VERSION 5.7 ;
  NOWIREEXTENSIONATPIN ON ;
  DIVIDERCHAR "/" ;
  BUSBITCHARS "[]" ;
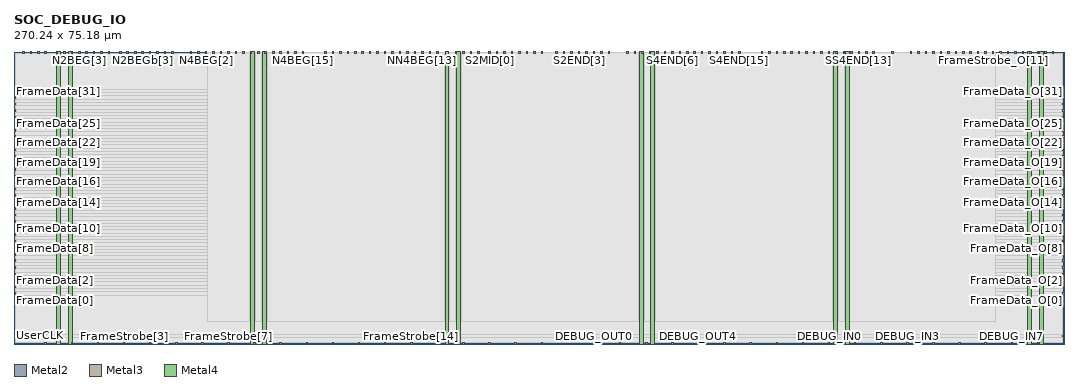
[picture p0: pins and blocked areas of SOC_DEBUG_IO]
MACRO SOC_DEBUG_IO
  CLASS BLOCK ;
  FOREIGN SOC_DEBUG_IO ;
  ORIGIN 0.000 0.000 ;
  SIZE 270.240 BY 75.180 ;
  PIN Co
    DIRECTION OUTPUT ;
    USE SIGNAL ;
    ANTENNADIFFAREA 2.314600 ;
    PORT
      LAYER Metal2 ;
        RECT 225.880 74.780 226.280 75.180 ;
    END
  END Co
  PIN DEBUG_IN0
    DIRECTION OUTPUT ;
    USE SIGNAL ;
    ANTENNADIFFAREA 2.647800 ;
    PORT
      LAYER Metal2 ;
        RECT 209.560 0.000 209.960 0.400 ;
    END
  END DEBUG_IN0
  PIN DEBUG_IN1
    DIRECTION OUTPUT ;
    USE SIGNAL ;
    ANTENNADIFFAREA 2.647800 ;
    PORT
      LAYER Metal2 ;
        RECT 216.280 0.000 216.680 0.400 ;
    END
  END DEBUG_IN1
  PIN DEBUG_IN2
    DIRECTION OUTPUT ;
    USE SIGNAL ;
    ANTENNADIFFAREA 2.647800 ;
    PORT
      LAYER Metal2 ;
        RECT 223.000 0.000 223.400 0.400 ;
    END
  END DEBUG_IN2
  PIN DEBUG_IN3
    DIRECTION OUTPUT ;
    USE SIGNAL ;
    ANTENNADIFFAREA 2.647800 ;
    PORT
      LAYER Metal2 ;
        RECT 229.720 0.000 230.120 0.400 ;
    END
  END DEBUG_IN3
  PIN DEBUG_IN4
    DIRECTION OUTPUT ;
    USE SIGNAL ;
    ANTENNADIFFAREA 2.647800 ;
    PORT
      LAYER Metal2 ;
        RECT 236.440 0.000 236.840 0.400 ;
    END
  END DEBUG_IN4
  PIN DEBUG_IN5
    DIRECTION OUTPUT ;
    USE SIGNAL ;
    ANTENNADIFFAREA 2.647800 ;
    PORT
      LAYER Metal2 ;
        RECT 243.160 0.000 243.560 0.400 ;
    END
  END DEBUG_IN5
  PIN DEBUG_IN6
    DIRECTION OUTPUT ;
    USE SIGNAL ;
    ANTENNADIFFAREA 2.647800 ;
    PORT
      LAYER Metal2 ;
        RECT 249.880 0.000 250.280 0.400 ;
    END
  END DEBUG_IN6
  PIN DEBUG_IN7
    DIRECTION OUTPUT ;
    USE SIGNAL ;
    ANTENNADIFFAREA 2.647800 ;
    PORT
      LAYER Metal2 ;
        RECT 256.600 0.000 257.000 0.400 ;
    END
  END DEBUG_IN7
  PIN DEBUG_OUT0
    DIRECTION INPUT ;
    USE SIGNAL ;
    ANTENNAGATEAREA 0.109200 ;
    ANTENNADIFFAREA 2.015400 ;
    PORT
      LAYER Metal2 ;
        RECT 149.080 0.000 149.480 0.400 ;
    END
  END DEBUG_OUT0
  PIN DEBUG_OUT1
    DIRECTION INPUT ;
    USE SIGNAL ;
    ANTENNAGATEAREA 0.109200 ;
    ANTENNADIFFAREA 2.015400 ;
    PORT
      LAYER Metal2 ;
        RECT 155.800 0.000 156.200 0.400 ;
    END
  END DEBUG_OUT1
  PIN DEBUG_OUT2
    DIRECTION INPUT ;
    USE SIGNAL ;
    ANTENNAGATEAREA 0.109200 ;
    ANTENNADIFFAREA 2.015400 ;
    PORT
      LAYER Metal2 ;
        RECT 162.520 0.000 162.920 0.400 ;
    END
  END DEBUG_OUT2
  PIN DEBUG_OUT3
    DIRECTION INPUT ;
    USE SIGNAL ;
    ANTENNAGATEAREA 0.109200 ;
    ANTENNADIFFAREA 2.015400 ;
    PORT
      LAYER Metal2 ;
        RECT 169.240 0.000 169.640 0.400 ;
    END
  END DEBUG_OUT3
  PIN DEBUG_OUT4
    DIRECTION INPUT ;
    USE SIGNAL ;
    ANTENNAGATEAREA 0.109200 ;
    ANTENNADIFFAREA 2.015400 ;
    PORT
      LAYER Metal2 ;
        RECT 175.960 0.000 176.360 0.400 ;
    END
  END DEBUG_OUT4
  PIN DEBUG_OUT5
    DIRECTION INPUT ;
    USE SIGNAL ;
    ANTENNAGATEAREA 0.109200 ;
    ANTENNADIFFAREA 2.015400 ;
    PORT
      LAYER Metal2 ;
        RECT 182.680 0.000 183.080 0.400 ;
    END
  END DEBUG_OUT5
  PIN DEBUG_OUT6
    DIRECTION INPUT ;
    USE SIGNAL ;
    ANTENNAGATEAREA 0.109200 ;
    ANTENNADIFFAREA 2.015400 ;
    PORT
      LAYER Metal2 ;
        RECT 189.400 0.000 189.800 0.400 ;
    END
  END DEBUG_OUT6
  PIN DEBUG_OUT7
    DIRECTION INPUT ;
    USE SIGNAL ;
    ANTENNAGATEAREA 0.109200 ;
    ANTENNADIFFAREA 2.015400 ;
    PORT
      LAYER Metal2 ;
        RECT 196.120 0.000 196.520 0.400 ;
    END
  END DEBUG_OUT7
  PIN FrameData[0]
    DIRECTION INPUT ;
    USE SIGNAL ;
    ANTENNAGATEAREA 0.722800 ;
    ANTENNADIFFAREA 8.061600 ;
    PORT
      LAYER Metal3 ;
        RECT 0.000 12.820 0.400 13.220 ;
    END
  END FrameData[0]
  PIN FrameData[10]
    DIRECTION INPUT ;
    USE SIGNAL ;
    ANTENNAGATEAREA 0.903500 ;
    ANTENNADIFFAREA 10.077000 ;
    PORT
      LAYER Metal3 ;
        RECT 0.000 29.620 0.400 30.020 ;
    END
  END FrameData[10]
  PIN FrameData[11]
    DIRECTION INPUT ;
    USE SIGNAL ;
    ANTENNAGATEAREA 0.903500 ;
    ANTENNADIFFAREA 10.077000 ;
    PORT
      LAYER Metal3 ;
        RECT 0.000 31.300 0.400 31.700 ;
    END
  END FrameData[11]
  PIN FrameData[12]
    DIRECTION INPUT ;
    USE SIGNAL ;
    ANTENNAGATEAREA 0.903500 ;
    ANTENNADIFFAREA 10.077000 ;
    PORT
      LAYER Metal3 ;
        RECT 0.000 32.980 0.400 33.380 ;
    END
  END FrameData[12]
  PIN FrameData[13]
    DIRECTION INPUT ;
    USE SIGNAL ;
    ANTENNAGATEAREA 0.903500 ;
    ANTENNADIFFAREA 10.077000 ;
    PORT
      LAYER Metal3 ;
        RECT 0.000 34.660 0.400 35.060 ;
    END
  END FrameData[13]
  PIN FrameData[14]
    DIRECTION INPUT ;
    USE SIGNAL ;
    ANTENNAGATEAREA 0.903500 ;
    ANTENNADIFFAREA 10.077000 ;
    PORT
      LAYER Metal3 ;
        RECT 0.000 36.340 0.400 36.740 ;
    END
  END FrameData[14]
  PIN FrameData[15]
    DIRECTION INPUT ;
    USE SIGNAL ;
    ANTENNAGATEAREA 0.903500 ;
    ANTENNADIFFAREA 10.077000 ;
    PORT
      LAYER Metal3 ;
        RECT 0.000 38.020 0.400 38.420 ;
    END
  END FrameData[15]
  PIN FrameData[16]
    DIRECTION INPUT ;
    USE SIGNAL ;
    ANTENNAGATEAREA 0.903500 ;
    ANTENNADIFFAREA 10.077000 ;
    PORT
      LAYER Metal3 ;
        RECT 0.000 39.700 0.400 40.100 ;
    END
  END FrameData[16]
  PIN FrameData[17]
    DIRECTION INPUT ;
    USE SIGNAL ;
    ANTENNAGATEAREA 0.903500 ;
    ANTENNADIFFAREA 10.077000 ;
    PORT
      LAYER Metal3 ;
        RECT 0.000 41.380 0.400 41.780 ;
    END
  END FrameData[17]
  PIN FrameData[18]
    DIRECTION INPUT ;
    USE SIGNAL ;
    ANTENNAGATEAREA 0.903500 ;
    ANTENNADIFFAREA 10.077000 ;
    PORT
      LAYER Metal3 ;
        RECT 0.000 43.060 0.400 43.460 ;
    END
  END FrameData[18]
  PIN FrameData[19]
    DIRECTION INPUT ;
    USE SIGNAL ;
    ANTENNAGATEAREA 0.903500 ;
    ANTENNADIFFAREA 10.077000 ;
    PORT
      LAYER Metal3 ;
        RECT 0.000 44.740 0.400 45.140 ;
    END
  END FrameData[19]
  PIN FrameData[1]
    DIRECTION INPUT ;
    USE SIGNAL ;
    ANTENNAGATEAREA 0.722800 ;
    ANTENNADIFFAREA 8.061600 ;
    PORT
      LAYER Metal3 ;
        RECT 0.000 14.500 0.400 14.900 ;
    END
  END FrameData[1]
  PIN FrameData[20]
    DIRECTION INPUT ;
    USE SIGNAL ;
    ANTENNAGATEAREA 0.903500 ;
    ANTENNADIFFAREA 10.077000 ;
    PORT
      LAYER Metal3 ;
        RECT 0.000 46.420 0.400 46.820 ;
    END
  END FrameData[20]
  PIN FrameData[21]
    DIRECTION INPUT ;
    USE SIGNAL ;
    ANTENNAGATEAREA 0.903500 ;
    ANTENNADIFFAREA 10.077000 ;
    PORT
      LAYER Metal3 ;
        RECT 0.000 48.100 0.400 48.500 ;
    END
  END FrameData[21]
  PIN FrameData[22]
    DIRECTION INPUT ;
    USE SIGNAL ;
    ANTENNAGATEAREA 0.903500 ;
    ANTENNADIFFAREA 10.077000 ;
    PORT
      LAYER Metal3 ;
        RECT 0.000 49.780 0.400 50.180 ;
    END
  END FrameData[22]
  PIN FrameData[23]
    DIRECTION INPUT ;
    USE SIGNAL ;
    ANTENNAGATEAREA 0.903500 ;
    ANTENNADIFFAREA 10.077000 ;
    PORT
      LAYER Metal3 ;
        RECT 0.000 51.460 0.400 51.860 ;
    END
  END FrameData[23]
  PIN FrameData[24]
    DIRECTION INPUT ;
    USE SIGNAL ;
    ANTENNAGATEAREA 0.903500 ;
    ANTENNADIFFAREA 10.077000 ;
    PORT
      LAYER Metal3 ;
        RECT 0.000 53.140 0.400 53.540 ;
    END
  END FrameData[24]
  PIN FrameData[25]
    DIRECTION INPUT ;
    USE SIGNAL ;
    ANTENNAGATEAREA 0.903500 ;
    ANTENNADIFFAREA 10.077000 ;
    PORT
      LAYER Metal3 ;
        RECT 0.000 54.820 0.400 55.220 ;
    END
  END FrameData[25]
  PIN FrameData[26]
    DIRECTION INPUT ;
    USE SIGNAL ;
    ANTENNAGATEAREA 0.903500 ;
    ANTENNADIFFAREA 10.077000 ;
    PORT
      LAYER Metal3 ;
        RECT 0.000 56.500 0.400 56.900 ;
    END
  END FrameData[26]
  PIN FrameData[27]
    DIRECTION INPUT ;
    USE SIGNAL ;
    ANTENNAGATEAREA 0.903500 ;
    ANTENNADIFFAREA 10.077000 ;
    PORT
      LAYER Metal3 ;
        RECT 0.000 58.180 0.400 58.580 ;
    END
  END FrameData[27]
  PIN FrameData[28]
    DIRECTION INPUT ;
    USE SIGNAL ;
    ANTENNAGATEAREA 0.903500 ;
    ANTENNADIFFAREA 10.077000 ;
    PORT
      LAYER Metal3 ;
        RECT 0.000 59.860 0.400 60.260 ;
    END
  END FrameData[28]
  PIN FrameData[29]
    DIRECTION INPUT ;
    USE SIGNAL ;
    ANTENNAGATEAREA 0.903500 ;
    ANTENNADIFFAREA 10.077000 ;
    PORT
      LAYER Metal3 ;
        RECT 0.000 61.540 0.400 61.940 ;
    END
  END FrameData[29]
  PIN FrameData[2]
    DIRECTION INPUT ;
    USE SIGNAL ;
    ANTENNAGATEAREA 0.722800 ;
    ANTENNADIFFAREA 8.061600 ;
    PORT
      LAYER Metal3 ;
        RECT 0.000 16.180 0.400 16.580 ;
    END
  END FrameData[2]
  PIN FrameData[30]
    DIRECTION INPUT ;
    USE SIGNAL ;
    ANTENNAGATEAREA 0.903500 ;
    ANTENNADIFFAREA 10.077000 ;
    PORT
      LAYER Metal3 ;
        RECT 0.000 63.220 0.400 63.620 ;
    END
  END FrameData[30]
  PIN FrameData[31]
    DIRECTION INPUT ;
    USE SIGNAL ;
    ANTENNAGATEAREA 0.903500 ;
    ANTENNADIFFAREA 10.077000 ;
    PORT
      LAYER Metal3 ;
        RECT 0.000 64.900 0.400 65.300 ;
    END
  END FrameData[31]
  PIN FrameData[3]
    DIRECTION INPUT ;
    USE SIGNAL ;
    ANTENNAGATEAREA 0.722800 ;
    ANTENNADIFFAREA 8.061600 ;
    PORT
      LAYER Metal3 ;
        RECT 0.000 17.860 0.400 18.260 ;
    END
  END FrameData[3]
  PIN FrameData[4]
    DIRECTION INPUT ;
    USE SIGNAL ;
    ANTENNAGATEAREA 0.722800 ;
    ANTENNADIFFAREA 8.061600 ;
    PORT
      LAYER Metal3 ;
        RECT 0.000 19.540 0.400 19.940 ;
    END
  END FrameData[4]
  PIN FrameData[5]
    DIRECTION INPUT ;
    USE SIGNAL ;
    ANTENNAGATEAREA 0.722800 ;
    ANTENNADIFFAREA 8.061600 ;
    PORT
      LAYER Metal3 ;
        RECT 0.000 21.220 0.400 21.620 ;
    END
  END FrameData[5]
  PIN FrameData[6]
    DIRECTION INPUT ;
    USE SIGNAL ;
    ANTENNAGATEAREA 0.722800 ;
    ANTENNADIFFAREA 8.061600 ;
    PORT
      LAYER Metal3 ;
        RECT 0.000 22.900 0.400 23.300 ;
    END
  END FrameData[6]
  PIN FrameData[7]
    DIRECTION INPUT ;
    USE SIGNAL ;
    ANTENNAGATEAREA 0.722800 ;
    ANTENNADIFFAREA 8.061600 ;
    PORT
      LAYER Metal3 ;
        RECT 0.000 24.580 0.400 24.980 ;
    END
  END FrameData[7]
  PIN FrameData[8]
    DIRECTION INPUT ;
    USE SIGNAL ;
    ANTENNAGATEAREA 0.722800 ;
    ANTENNADIFFAREA 8.061600 ;
    PORT
      LAYER Metal3 ;
        RECT 0.000 26.260 0.400 26.660 ;
    END
  END FrameData[8]
  PIN FrameData[9]
    DIRECTION INPUT ;
    USE SIGNAL ;
    ANTENNAGATEAREA 0.722800 ;
    ANTENNADIFFAREA 8.061600 ;
    PORT
      LAYER Metal3 ;
        RECT 0.000 27.940 0.400 28.340 ;
    END
  END FrameData[9]
  PIN FrameData_O[0]
    DIRECTION OUTPUT ;
    USE SIGNAL ;
    ANTENNADIFFAREA 2.724000 ;
    PORT
      LAYER Metal3 ;
        RECT 269.840 12.820 270.240 13.220 ;
    END
  END FrameData_O[0]
  PIN FrameData_O[10]
    DIRECTION OUTPUT ;
    USE SIGNAL ;
    ANTENNADIFFAREA 2.724000 ;
    PORT
      LAYER Metal3 ;
        RECT 269.840 29.620 270.240 30.020 ;
    END
  END FrameData_O[10]
  PIN FrameData_O[11]
    DIRECTION OUTPUT ;
    USE SIGNAL ;
    ANTENNADIFFAREA 2.724000 ;
    PORT
      LAYER Metal3 ;
        RECT 269.840 31.300 270.240 31.700 ;
    END
  END FrameData_O[11]
  PIN FrameData_O[12]
    DIRECTION OUTPUT ;
    USE SIGNAL ;
    ANTENNADIFFAREA 2.724000 ;
    PORT
      LAYER Metal3 ;
        RECT 269.840 32.980 270.240 33.380 ;
    END
  END FrameData_O[12]
  PIN FrameData_O[13]
    DIRECTION OUTPUT ;
    USE SIGNAL ;
    ANTENNADIFFAREA 2.724000 ;
    PORT
      LAYER Metal3 ;
        RECT 269.840 34.660 270.240 35.060 ;
    END
  END FrameData_O[13]
  PIN FrameData_O[14]
    DIRECTION OUTPUT ;
    USE SIGNAL ;
    ANTENNADIFFAREA 2.724000 ;
    PORT
      LAYER Metal3 ;
        RECT 269.840 36.340 270.240 36.740 ;
    END
  END FrameData_O[14]
  PIN FrameData_O[15]
    DIRECTION OUTPUT ;
    USE SIGNAL ;
    ANTENNADIFFAREA 2.724000 ;
    PORT
      LAYER Metal3 ;
        RECT 269.840 38.020 270.240 38.420 ;
    END
  END FrameData_O[15]
  PIN FrameData_O[16]
    DIRECTION OUTPUT ;
    USE SIGNAL ;
    ANTENNADIFFAREA 2.724000 ;
    PORT
      LAYER Metal3 ;
        RECT 269.840 39.700 270.240 40.100 ;
    END
  END FrameData_O[16]
  PIN FrameData_O[17]
    DIRECTION OUTPUT ;
    USE SIGNAL ;
    ANTENNADIFFAREA 2.724000 ;
    PORT
      LAYER Metal3 ;
        RECT 269.840 41.380 270.240 41.780 ;
    END
  END FrameData_O[17]
  PIN FrameData_O[18]
    DIRECTION OUTPUT ;
    USE SIGNAL ;
    ANTENNADIFFAREA 2.724000 ;
    PORT
      LAYER Metal3 ;
        RECT 269.840 43.060 270.240 43.460 ;
    END
  END FrameData_O[18]
  PIN FrameData_O[19]
    DIRECTION OUTPUT ;
    USE SIGNAL ;
    ANTENNADIFFAREA 2.724000 ;
    PORT
      LAYER Metal3 ;
        RECT 269.840 44.740 270.240 45.140 ;
    END
  END FrameData_O[19]
  PIN FrameData_O[1]
    DIRECTION OUTPUT ;
    USE SIGNAL ;
    ANTENNADIFFAREA 2.724000 ;
    PORT
      LAYER Metal3 ;
        RECT 269.840 14.500 270.240 14.900 ;
    END
  END FrameData_O[1]
  PIN FrameData_O[20]
    DIRECTION OUTPUT ;
    USE SIGNAL ;
    ANTENNADIFFAREA 2.724000 ;
    PORT
      LAYER Metal3 ;
        RECT 269.840 46.420 270.240 46.820 ;
    END
  END FrameData_O[20]
  PIN FrameData_O[21]
    DIRECTION OUTPUT ;
    USE SIGNAL ;
    ANTENNADIFFAREA 2.724000 ;
    PORT
      LAYER Metal3 ;
        RECT 269.840 48.100 270.240 48.500 ;
    END
  END FrameData_O[21]
  PIN FrameData_O[22]
    DIRECTION OUTPUT ;
    USE SIGNAL ;
    ANTENNADIFFAREA 2.724000 ;
    PORT
      LAYER Metal3 ;
        RECT 269.840 49.780 270.240 50.180 ;
    END
  END FrameData_O[22]
  PIN FrameData_O[23]
    DIRECTION OUTPUT ;
    USE SIGNAL ;
    ANTENNADIFFAREA 2.724000 ;
    PORT
      LAYER Metal3 ;
        RECT 269.840 51.460 270.240 51.860 ;
    END
  END FrameData_O[23]
  PIN FrameData_O[24]
    DIRECTION OUTPUT ;
    USE SIGNAL ;
    ANTENNADIFFAREA 2.724000 ;
    PORT
      LAYER Metal3 ;
        RECT 269.840 53.140 270.240 53.540 ;
    END
  END FrameData_O[24]
  PIN FrameData_O[25]
    DIRECTION OUTPUT ;
    USE SIGNAL ;
    ANTENNADIFFAREA 2.724000 ;
    PORT
      LAYER Metal3 ;
        RECT 269.840 54.820 270.240 55.220 ;
    END
  END FrameData_O[25]
  PIN FrameData_O[26]
    DIRECTION OUTPUT ;
    USE SIGNAL ;
    ANTENNADIFFAREA 2.724000 ;
    PORT
      LAYER Metal3 ;
        RECT 269.840 56.500 270.240 56.900 ;
    END
  END FrameData_O[26]
  PIN FrameData_O[27]
    DIRECTION OUTPUT ;
    USE SIGNAL ;
    ANTENNADIFFAREA 2.724000 ;
    PORT
      LAYER Metal3 ;
        RECT 269.840 58.180 270.240 58.580 ;
    END
  END FrameData_O[27]
  PIN FrameData_O[28]
    DIRECTION OUTPUT ;
    USE SIGNAL ;
    ANTENNADIFFAREA 2.724000 ;
    PORT
      LAYER Metal3 ;
        RECT 269.840 59.860 270.240 60.260 ;
    END
  END FrameData_O[28]
  PIN FrameData_O[29]
    DIRECTION OUTPUT ;
    USE SIGNAL ;
    ANTENNADIFFAREA 2.724000 ;
    PORT
      LAYER Metal3 ;
        RECT 269.840 61.540 270.240 61.940 ;
    END
  END FrameData_O[29]
  PIN FrameData_O[2]
    DIRECTION OUTPUT ;
    USE SIGNAL ;
    ANTENNADIFFAREA 2.724000 ;
    PORT
      LAYER Metal3 ;
        RECT 269.840 16.180 270.240 16.580 ;
    END
  END FrameData_O[2]
  PIN FrameData_O[30]
    DIRECTION OUTPUT ;
    USE SIGNAL ;
    ANTENNADIFFAREA 2.724000 ;
    PORT
      LAYER Metal3 ;
        RECT 269.840 63.220 270.240 63.620 ;
    END
  END FrameData_O[30]
  PIN FrameData_O[31]
    DIRECTION OUTPUT ;
    USE SIGNAL ;
    ANTENNADIFFAREA 2.724000 ;
    PORT
      LAYER Metal3 ;
        RECT 269.840 64.900 270.240 65.300 ;
    END
  END FrameData_O[31]
  PIN FrameData_O[3]
    DIRECTION OUTPUT ;
    USE SIGNAL ;
    ANTENNADIFFAREA 2.724000 ;
    PORT
      LAYER Metal3 ;
        RECT 269.840 17.860 270.240 18.260 ;
    END
  END FrameData_O[3]
  PIN FrameData_O[4]
    DIRECTION OUTPUT ;
    USE SIGNAL ;
    ANTENNADIFFAREA 2.724000 ;
    PORT
      LAYER Metal3 ;
        RECT 269.840 19.540 270.240 19.940 ;
    END
  END FrameData_O[4]
  PIN FrameData_O[5]
    DIRECTION OUTPUT ;
    USE SIGNAL ;
    ANTENNADIFFAREA 2.724000 ;
    PORT
      LAYER Metal3 ;
        RECT 269.840 21.220 270.240 21.620 ;
    END
  END FrameData_O[5]
  PIN FrameData_O[6]
    DIRECTION OUTPUT ;
    USE SIGNAL ;
    ANTENNADIFFAREA 2.724000 ;
    PORT
      LAYER Metal3 ;
        RECT 269.840 22.900 270.240 23.300 ;
    END
  END FrameData_O[6]
  PIN FrameData_O[7]
    DIRECTION OUTPUT ;
    USE SIGNAL ;
    ANTENNADIFFAREA 2.724000 ;
    PORT
      LAYER Metal3 ;
        RECT 269.840 24.580 270.240 24.980 ;
    END
  END FrameData_O[7]
  PIN FrameData_O[8]
    DIRECTION OUTPUT ;
    USE SIGNAL ;
    ANTENNADIFFAREA 2.724000 ;
    PORT
      LAYER Metal3 ;
        RECT 269.840 26.260 270.240 26.660 ;
    END
  END FrameData_O[8]
  PIN FrameData_O[9]
    DIRECTION OUTPUT ;
    USE SIGNAL ;
    ANTENNADIFFAREA 2.724000 ;
    PORT
      LAYER Metal3 ;
        RECT 269.840 27.940 270.240 28.340 ;
    END
  END FrameData_O[9]
  PIN FrameStrobe[0]
    DIRECTION INPUT ;
    USE SIGNAL ;
    ANTENNAGATEAREA 11.745500 ;
    ANTENNADIFFAREA 66.508202 ;
    PORT
      LAYER Metal2 ;
        RECT 7.960 0.000 8.360 0.400 ;
    END
  END FrameStrobe[0]
  PIN FrameStrobe[10]
    DIRECTION INPUT ;
    USE SIGNAL ;
    ANTENNAGATEAREA 0.180700 ;
    ANTENNADIFFAREA 2.015400 ;
    PORT
      LAYER Metal2 ;
        RECT 75.160 0.000 75.560 0.400 ;
    END
  END FrameStrobe[10]
  PIN FrameStrobe[11]
    DIRECTION INPUT ;
    USE SIGNAL ;
    ANTENNAGATEAREA 0.180700 ;
    ANTENNADIFFAREA 2.015400 ;
    PORT
      LAYER Metal2 ;
        RECT 81.880 0.000 82.280 0.400 ;
    END
  END FrameStrobe[11]
  PIN FrameStrobe[12]
    DIRECTION INPUT ;
    USE SIGNAL ;
    ANTENNAGATEAREA 0.180700 ;
    ANTENNADIFFAREA 2.015400 ;
    PORT
      LAYER Metal2 ;
        RECT 88.600 0.000 89.000 0.400 ;
    END
  END FrameStrobe[12]
  PIN FrameStrobe[13]
    DIRECTION INPUT ;
    USE SIGNAL ;
    ANTENNAGATEAREA 0.180700 ;
    ANTENNADIFFAREA 2.015400 ;
    PORT
      LAYER Metal2 ;
        RECT 95.320 0.000 95.720 0.400 ;
    END
  END FrameStrobe[13]
  PIN FrameStrobe[14]
    DIRECTION INPUT ;
    USE SIGNAL ;
    ANTENNAGATEAREA 0.180700 ;
    ANTENNADIFFAREA 2.015400 ;
    PORT
      LAYER Metal2 ;
        RECT 102.040 0.000 102.440 0.400 ;
    END
  END FrameStrobe[14]
  PIN FrameStrobe[15]
    DIRECTION INPUT ;
    USE SIGNAL ;
    ANTENNAGATEAREA 0.180700 ;
    ANTENNADIFFAREA 2.015400 ;
    PORT
      LAYER Metal2 ;
        RECT 108.760 0.000 109.160 0.400 ;
    END
  END FrameStrobe[15]
  PIN FrameStrobe[16]
    DIRECTION INPUT ;
    USE SIGNAL ;
    ANTENNAGATEAREA 0.180700 ;
    ANTENNADIFFAREA 2.015400 ;
    PORT
      LAYER Metal2 ;
        RECT 115.480 0.000 115.880 0.400 ;
    END
  END FrameStrobe[16]
  PIN FrameStrobe[17]
    DIRECTION INPUT ;
    USE SIGNAL ;
    ANTENNAGATEAREA 0.180700 ;
    ANTENNADIFFAREA 2.015400 ;
    PORT
      LAYER Metal2 ;
        RECT 122.200 0.000 122.600 0.400 ;
    END
  END FrameStrobe[17]
  PIN FrameStrobe[18]
    DIRECTION INPUT ;
    USE SIGNAL ;
    ANTENNAGATEAREA 0.180700 ;
    ANTENNADIFFAREA 2.015400 ;
    PORT
      LAYER Metal2 ;
        RECT 128.920 0.000 129.320 0.400 ;
    END
  END FrameStrobe[18]
  PIN FrameStrobe[19]
    DIRECTION INPUT ;
    USE SIGNAL ;
    ANTENNAGATEAREA 0.180700 ;
    ANTENNADIFFAREA 2.015400 ;
    PORT
      LAYER Metal2 ;
        RECT 135.640 0.000 136.040 0.400 ;
    END
  END FrameStrobe[19]
  PIN FrameStrobe[1]
    DIRECTION INPUT ;
    USE SIGNAL ;
    ANTENNAGATEAREA 11.745500 ;
    ANTENNADIFFAREA 66.508202 ;
    PORT
      LAYER Metal2 ;
        RECT 14.680 0.000 15.080 0.400 ;
    END
  END FrameStrobe[1]
  PIN FrameStrobe[2]
    DIRECTION INPUT ;
    USE SIGNAL ;
    ANTENNAGATEAREA 11.745500 ;
    ANTENNADIFFAREA 66.508202 ;
    PORT
      LAYER Metal2 ;
        RECT 21.400 0.000 21.800 0.400 ;
    END
  END FrameStrobe[2]
  PIN FrameStrobe[3]
    DIRECTION INPUT ;
    USE SIGNAL ;
    ANTENNAGATEAREA 8.131500 ;
    ANTENNADIFFAREA 46.354198 ;
    PORT
      LAYER Metal2 ;
        RECT 28.120 0.000 28.520 0.400 ;
    END
  END FrameStrobe[3]
  PIN FrameStrobe[4]
    DIRECTION INPUT ;
    USE SIGNAL ;
    ANTENNAGATEAREA 0.180700 ;
    ANTENNADIFFAREA 2.015400 ;
    PORT
      LAYER Metal2 ;
        RECT 34.840 0.000 35.240 0.400 ;
    END
  END FrameStrobe[4]
  PIN FrameStrobe[5]
    DIRECTION INPUT ;
    USE SIGNAL ;
    ANTENNAGATEAREA 0.180700 ;
    ANTENNADIFFAREA 2.015400 ;
    PORT
      LAYER Metal2 ;
        RECT 41.560 0.000 41.960 0.400 ;
    END
  END FrameStrobe[5]
  PIN FrameStrobe[6]
    DIRECTION INPUT ;
    USE SIGNAL ;
    ANTENNAGATEAREA 0.180700 ;
    ANTENNADIFFAREA 2.015400 ;
    PORT
      LAYER Metal2 ;
        RECT 48.280 0.000 48.680 0.400 ;
    END
  END FrameStrobe[6]
  PIN FrameStrobe[7]
    DIRECTION INPUT ;
    USE SIGNAL ;
    ANTENNAGATEAREA 0.180700 ;
    ANTENNADIFFAREA 2.015400 ;
    PORT
      LAYER Metal2 ;
        RECT 55.000 0.000 55.400 0.400 ;
    END
  END FrameStrobe[7]
  PIN FrameStrobe[8]
    DIRECTION INPUT ;
    USE SIGNAL ;
    ANTENNAGATEAREA 0.180700 ;
    ANTENNADIFFAREA 2.015400 ;
    PORT
      LAYER Metal2 ;
        RECT 61.720 0.000 62.120 0.400 ;
    END
  END FrameStrobe[8]
  PIN FrameStrobe[9]
    DIRECTION INPUT ;
    USE SIGNAL ;
    ANTENNAGATEAREA 0.180700 ;
    ANTENNADIFFAREA 2.015400 ;
    PORT
      LAYER Metal2 ;
        RECT 68.440 0.000 68.840 0.400 ;
    END
  END FrameStrobe[9]
  PIN FrameStrobe_O[0]
    DIRECTION OUTPUT ;
    USE SIGNAL ;
    ANTENNADIFFAREA 2.724000 ;
    PORT
      LAYER Metal2 ;
        RECT 230.680 74.780 231.080 75.180 ;
    END
  END FrameStrobe_O[0]
  PIN FrameStrobe_O[10]
    DIRECTION OUTPUT ;
    USE SIGNAL ;
    ANTENNADIFFAREA 2.724000 ;
    PORT
      LAYER Metal2 ;
        RECT 249.880 74.780 250.280 75.180 ;
    END
  END FrameStrobe_O[10]
  PIN FrameStrobe_O[11]
    DIRECTION OUTPUT ;
    USE SIGNAL ;
    ANTENNADIFFAREA 2.724000 ;
    PORT
      LAYER Metal2 ;
        RECT 251.800 74.780 252.200 75.180 ;
    END
  END FrameStrobe_O[11]
  PIN FrameStrobe_O[12]
    DIRECTION OUTPUT ;
    USE SIGNAL ;
    ANTENNADIFFAREA 2.724000 ;
    PORT
      LAYER Metal2 ;
        RECT 253.720 74.780 254.120 75.180 ;
    END
  END FrameStrobe_O[12]
  PIN FrameStrobe_O[13]
    DIRECTION OUTPUT ;
    USE SIGNAL ;
    ANTENNADIFFAREA 2.724000 ;
    PORT
      LAYER Metal2 ;
        RECT 255.640 74.780 256.040 75.180 ;
    END
  END FrameStrobe_O[13]
  PIN FrameStrobe_O[14]
    DIRECTION OUTPUT ;
    USE SIGNAL ;
    ANTENNADIFFAREA 2.724000 ;
    PORT
      LAYER Metal2 ;
        RECT 257.560 74.780 257.960 75.180 ;
    END
  END FrameStrobe_O[14]
  PIN FrameStrobe_O[15]
    DIRECTION OUTPUT ;
    USE SIGNAL ;
    ANTENNADIFFAREA 2.724000 ;
    PORT
      LAYER Metal2 ;
        RECT 259.480 74.780 259.880 75.180 ;
    END
  END FrameStrobe_O[15]
  PIN FrameStrobe_O[16]
    DIRECTION OUTPUT ;
    USE SIGNAL ;
    ANTENNADIFFAREA 2.724000 ;
    PORT
      LAYER Metal2 ;
        RECT 261.400 74.780 261.800 75.180 ;
    END
  END FrameStrobe_O[16]
  PIN FrameStrobe_O[17]
    DIRECTION OUTPUT ;
    USE SIGNAL ;
    ANTENNADIFFAREA 2.724000 ;
    PORT
      LAYER Metal2 ;
        RECT 263.320 74.780 263.720 75.180 ;
    END
  END FrameStrobe_O[17]
  PIN FrameStrobe_O[18]
    DIRECTION OUTPUT ;
    USE SIGNAL ;
    ANTENNADIFFAREA 2.724000 ;
    PORT
      LAYER Metal2 ;
        RECT 265.240 74.780 265.640 75.180 ;
    END
  END FrameStrobe_O[18]
  PIN FrameStrobe_O[19]
    DIRECTION OUTPUT ;
    USE SIGNAL ;
    ANTENNADIFFAREA 2.724000 ;
    PORT
      LAYER Metal2 ;
        RECT 267.160 74.780 267.560 75.180 ;
    END
  END FrameStrobe_O[19]
  PIN FrameStrobe_O[1]
    DIRECTION OUTPUT ;
    USE SIGNAL ;
    ANTENNADIFFAREA 2.724000 ;
    PORT
      LAYER Metal2 ;
        RECT 232.600 74.780 233.000 75.180 ;
    END
  END FrameStrobe_O[1]
  PIN FrameStrobe_O[2]
    DIRECTION OUTPUT ;
    USE SIGNAL ;
    ANTENNADIFFAREA 2.724000 ;
    PORT
      LAYER Metal2 ;
        RECT 234.520 74.780 234.920 75.180 ;
    END
  END FrameStrobe_O[2]
  PIN FrameStrobe_O[3]
    DIRECTION OUTPUT ;
    USE SIGNAL ;
    ANTENNADIFFAREA 2.724000 ;
    PORT
      LAYER Metal2 ;
        RECT 236.440 74.780 236.840 75.180 ;
    END
  END FrameStrobe_O[3]
  PIN FrameStrobe_O[4]
    DIRECTION OUTPUT ;
    USE SIGNAL ;
    ANTENNADIFFAREA 2.724000 ;
    PORT
      LAYER Metal2 ;
        RECT 238.360 74.780 238.760 75.180 ;
    END
  END FrameStrobe_O[4]
  PIN FrameStrobe_O[5]
    DIRECTION OUTPUT ;
    USE SIGNAL ;
    ANTENNADIFFAREA 2.724000 ;
    PORT
      LAYER Metal2 ;
        RECT 240.280 74.780 240.680 75.180 ;
    END
  END FrameStrobe_O[5]
  PIN FrameStrobe_O[6]
    DIRECTION OUTPUT ;
    USE SIGNAL ;
    ANTENNADIFFAREA 2.724000 ;
    PORT
      LAYER Metal2 ;
        RECT 242.200 74.780 242.600 75.180 ;
    END
  END FrameStrobe_O[6]
  PIN FrameStrobe_O[7]
    DIRECTION OUTPUT ;
    USE SIGNAL ;
    ANTENNADIFFAREA 2.724000 ;
    PORT
      LAYER Metal2 ;
        RECT 244.120 74.780 244.520 75.180 ;
    END
  END FrameStrobe_O[7]
  PIN FrameStrobe_O[8]
    DIRECTION OUTPUT ;
    USE SIGNAL ;
    ANTENNADIFFAREA 2.724000 ;
    PORT
      LAYER Metal2 ;
        RECT 246.040 74.780 246.440 75.180 ;
    END
  END FrameStrobe_O[8]
  PIN FrameStrobe_O[9]
    DIRECTION OUTPUT ;
    USE SIGNAL ;
    ANTENNADIFFAREA 2.724000 ;
    PORT
      LAYER Metal2 ;
        RECT 247.960 74.780 248.360 75.180 ;
    END
  END FrameStrobe_O[9]
  PIN N1BEG[0]
    DIRECTION OUTPUT ;
    USE SIGNAL ;
    ANTENNADIFFAREA 2.724000 ;
    PORT
      LAYER Metal2 ;
        RECT 2.200 74.780 2.600 75.180 ;
    END
  END N1BEG[0]
  PIN N1BEG[1]
    DIRECTION OUTPUT ;
    USE SIGNAL ;
    ANTENNADIFFAREA 2.724000 ;
    PORT
      LAYER Metal2 ;
        RECT 4.120 74.780 4.520 75.180 ;
    END
  END N1BEG[1]
  PIN N1BEG[2]
    DIRECTION OUTPUT ;
    USE SIGNAL ;
    ANTENNADIFFAREA 2.724000 ;
    PORT
      LAYER Metal2 ;
        RECT 6.040 74.780 6.440 75.180 ;
    END
  END N1BEG[2]
  PIN N1BEG[3]
    DIRECTION OUTPUT ;
    USE SIGNAL ;
    ANTENNADIFFAREA 2.724000 ;
    PORT
      LAYER Metal2 ;
        RECT 7.960 74.780 8.360 75.180 ;
    END
  END N1BEG[3]
  PIN N2BEG[0]
    DIRECTION OUTPUT ;
    USE SIGNAL ;
    ANTENNADIFFAREA 2.724000 ;
    PORT
      LAYER Metal2 ;
        RECT 10.840 74.780 11.240 75.180 ;
    END
  END N2BEG[0]
  PIN N2BEG[1]
    DIRECTION OUTPUT ;
    USE SIGNAL ;
    ANTENNADIFFAREA 2.724000 ;
    PORT
      LAYER Metal2 ;
        RECT 12.760 74.780 13.160 75.180 ;
    END
  END N2BEG[1]
  PIN N2BEG[2]
    DIRECTION OUTPUT ;
    USE SIGNAL ;
    ANTENNADIFFAREA 2.724000 ;
    PORT
      LAYER Metal2 ;
        RECT 14.680 74.780 15.080 75.180 ;
    END
  END N2BEG[2]
  PIN N2BEG[3]
    DIRECTION OUTPUT ;
    USE SIGNAL ;
    ANTENNADIFFAREA 2.724000 ;
    PORT
      LAYER Metal2 ;
        RECT 16.600 74.780 17.000 75.180 ;
    END
  END N2BEG[3]
  PIN N2BEG[4]
    DIRECTION OUTPUT ;
    USE SIGNAL ;
    ANTENNADIFFAREA 2.724000 ;
    PORT
      LAYER Metal2 ;
        RECT 18.520 74.780 18.920 75.180 ;
    END
  END N2BEG[4]
  PIN N2BEG[5]
    DIRECTION OUTPUT ;
    USE SIGNAL ;
    ANTENNADIFFAREA 2.724000 ;
    PORT
      LAYER Metal2 ;
        RECT 20.440 74.780 20.840 75.180 ;
    END
  END N2BEG[5]
  PIN N2BEG[6]
    DIRECTION OUTPUT ;
    USE SIGNAL ;
    ANTENNADIFFAREA 2.724000 ;
    PORT
      LAYER Metal2 ;
        RECT 22.360 74.780 22.760 75.180 ;
    END
  END N2BEG[6]
  PIN N2BEG[7]
    DIRECTION OUTPUT ;
    USE SIGNAL ;
    ANTENNADIFFAREA 2.724000 ;
    PORT
      LAYER Metal2 ;
        RECT 24.280 74.780 24.680 75.180 ;
    END
  END N2BEG[7]
  PIN N2BEGb[0]
    DIRECTION OUTPUT ;
    USE SIGNAL ;
    ANTENNADIFFAREA 2.724000 ;
    PORT
      LAYER Metal2 ;
        RECT 27.160 74.780 27.560 75.180 ;
    END
  END N2BEGb[0]
  PIN N2BEGb[1]
    DIRECTION OUTPUT ;
    USE SIGNAL ;
    ANTENNADIFFAREA 2.724000 ;
    PORT
      LAYER Metal2 ;
        RECT 29.080 74.780 29.480 75.180 ;
    END
  END N2BEGb[1]
  PIN N2BEGb[2]
    DIRECTION OUTPUT ;
    USE SIGNAL ;
    ANTENNADIFFAREA 2.724000 ;
    PORT
      LAYER Metal2 ;
        RECT 31.000 74.780 31.400 75.180 ;
    END
  END N2BEGb[2]
  PIN N2BEGb[3]
    DIRECTION OUTPUT ;
    USE SIGNAL ;
    ANTENNADIFFAREA 2.724000 ;
    PORT
      LAYER Metal2 ;
        RECT 32.920 74.780 33.320 75.180 ;
    END
  END N2BEGb[3]
  PIN N2BEGb[4]
    DIRECTION OUTPUT ;
    USE SIGNAL ;
    ANTENNADIFFAREA 2.724000 ;
    PORT
      LAYER Metal2 ;
        RECT 34.840 74.780 35.240 75.180 ;
    END
  END N2BEGb[4]
  PIN N2BEGb[5]
    DIRECTION OUTPUT ;
    USE SIGNAL ;
    ANTENNADIFFAREA 2.724000 ;
    PORT
      LAYER Metal2 ;
        RECT 36.760 74.780 37.160 75.180 ;
    END
  END N2BEGb[5]
  PIN N2BEGb[6]
    DIRECTION OUTPUT ;
    USE SIGNAL ;
    ANTENNADIFFAREA 2.724000 ;
    PORT
      LAYER Metal2 ;
        RECT 38.680 74.780 39.080 75.180 ;
    END
  END N2BEGb[6]
  PIN N2BEGb[7]
    DIRECTION OUTPUT ;
    USE SIGNAL ;
    ANTENNADIFFAREA 2.724000 ;
    PORT
      LAYER Metal2 ;
        RECT 40.600 74.780 41.000 75.180 ;
    END
  END N2BEGb[7]
  PIN N4BEG[0]
    DIRECTION OUTPUT ;
    USE SIGNAL ;
    ANTENNADIFFAREA 2.724000 ;
    PORT
      LAYER Metal2 ;
        RECT 45.400 74.780 45.800 75.180 ;
    END
  END N4BEG[0]
  PIN N4BEG[10]
    DIRECTION OUTPUT ;
    USE SIGNAL ;
    ANTENNADIFFAREA 2.724000 ;
    PORT
      LAYER Metal2 ;
        RECT 64.600 74.780 65.000 75.180 ;
    END
  END N4BEG[10]
  PIN N4BEG[11]
    DIRECTION OUTPUT ;
    USE SIGNAL ;
    ANTENNADIFFAREA 2.724000 ;
    PORT
      LAYER Metal2 ;
        RECT 66.520 74.780 66.920 75.180 ;
    END
  END N4BEG[11]
  PIN N4BEG[12]
    DIRECTION OUTPUT ;
    USE SIGNAL ;
    ANTENNADIFFAREA 2.724000 ;
    PORT
      LAYER Metal2 ;
        RECT 68.440 74.780 68.840 75.180 ;
    END
  END N4BEG[12]
  PIN N4BEG[13]
    DIRECTION OUTPUT ;
    USE SIGNAL ;
    ANTENNADIFFAREA 2.724000 ;
    PORT
      LAYER Metal2 ;
        RECT 70.360 74.780 70.760 75.180 ;
    END
  END N4BEG[13]
  PIN N4BEG[14]
    DIRECTION OUTPUT ;
    USE SIGNAL ;
    ANTENNADIFFAREA 2.724000 ;
    PORT
      LAYER Metal2 ;
        RECT 72.280 74.780 72.680 75.180 ;
    END
  END N4BEG[14]
  PIN N4BEG[15]
    DIRECTION OUTPUT ;
    USE SIGNAL ;
    ANTENNADIFFAREA 2.724000 ;
    PORT
      LAYER Metal2 ;
        RECT 74.200 74.780 74.600 75.180 ;
    END
  END N4BEG[15]
  PIN N4BEG[1]
    DIRECTION OUTPUT ;
    USE SIGNAL ;
    ANTENNADIFFAREA 2.724000 ;
    PORT
      LAYER Metal2 ;
        RECT 47.320 74.780 47.720 75.180 ;
    END
  END N4BEG[1]
  PIN N4BEG[2]
    DIRECTION OUTPUT ;
    USE SIGNAL ;
    ANTENNADIFFAREA 2.724000 ;
    PORT
      LAYER Metal2 ;
        RECT 49.240 74.780 49.640 75.180 ;
    END
  END N4BEG[2]
  PIN N4BEG[3]
    DIRECTION OUTPUT ;
    USE SIGNAL ;
    ANTENNADIFFAREA 2.724000 ;
    PORT
      LAYER Metal2 ;
        RECT 51.160 74.780 51.560 75.180 ;
    END
  END N4BEG[3]
  PIN N4BEG[4]
    DIRECTION OUTPUT ;
    USE SIGNAL ;
    ANTENNADIFFAREA 2.724000 ;
    PORT
      LAYER Metal2 ;
        RECT 53.080 74.780 53.480 75.180 ;
    END
  END N4BEG[4]
  PIN N4BEG[5]
    DIRECTION OUTPUT ;
    USE SIGNAL ;
    ANTENNADIFFAREA 2.724000 ;
    PORT
      LAYER Metal2 ;
        RECT 55.000 74.780 55.400 75.180 ;
    END
  END N4BEG[5]
  PIN N4BEG[6]
    DIRECTION OUTPUT ;
    USE SIGNAL ;
    ANTENNADIFFAREA 2.724000 ;
    PORT
      LAYER Metal2 ;
        RECT 56.920 74.780 57.320 75.180 ;
    END
  END N4BEG[6]
  PIN N4BEG[7]
    DIRECTION OUTPUT ;
    USE SIGNAL ;
    ANTENNADIFFAREA 2.724000 ;
    PORT
      LAYER Metal2 ;
        RECT 58.840 74.780 59.240 75.180 ;
    END
  END N4BEG[7]
  PIN N4BEG[8]
    DIRECTION OUTPUT ;
    USE SIGNAL ;
    ANTENNADIFFAREA 2.724000 ;
    PORT
      LAYER Metal2 ;
        RECT 60.760 74.780 61.160 75.180 ;
    END
  END N4BEG[8]
  PIN N4BEG[9]
    DIRECTION OUTPUT ;
    USE SIGNAL ;
    ANTENNADIFFAREA 2.724000 ;
    PORT
      LAYER Metal2 ;
        RECT 62.680 74.780 63.080 75.180 ;
    END
  END N4BEG[9]
  PIN NN4BEG[0]
    DIRECTION OUTPUT ;
    USE SIGNAL ;
    ANTENNADIFFAREA 2.724000 ;
    PORT
      LAYER Metal2 ;
        RECT 79.960 74.780 80.360 75.180 ;
    END
  END NN4BEG[0]
  PIN NN4BEG[10]
    DIRECTION OUTPUT ;
    USE SIGNAL ;
    ANTENNADIFFAREA 2.724000 ;
    PORT
      LAYER Metal2 ;
        RECT 99.160 74.780 99.560 75.180 ;
    END
  END NN4BEG[10]
  PIN NN4BEG[11]
    DIRECTION OUTPUT ;
    USE SIGNAL ;
    ANTENNADIFFAREA 2.724000 ;
    PORT
      LAYER Metal2 ;
        RECT 101.080 74.780 101.480 75.180 ;
    END
  END NN4BEG[11]
  PIN NN4BEG[12]
    DIRECTION OUTPUT ;
    USE SIGNAL ;
    ANTENNADIFFAREA 2.724000 ;
    PORT
      LAYER Metal2 ;
        RECT 103.000 74.780 103.400 75.180 ;
    END
  END NN4BEG[12]
  PIN NN4BEG[13]
    DIRECTION OUTPUT ;
    USE SIGNAL ;
    ANTENNADIFFAREA 2.724000 ;
    PORT
      LAYER Metal2 ;
        RECT 104.920 74.780 105.320 75.180 ;
    END
  END NN4BEG[13]
  PIN NN4BEG[14]
    DIRECTION OUTPUT ;
    USE SIGNAL ;
    ANTENNADIFFAREA 2.724000 ;
    PORT
      LAYER Metal2 ;
        RECT 106.840 74.780 107.240 75.180 ;
    END
  END NN4BEG[14]
  PIN NN4BEG[15]
    DIRECTION OUTPUT ;
    USE SIGNAL ;
    ANTENNADIFFAREA 2.724000 ;
    PORT
      LAYER Metal2 ;
        RECT 108.760 74.780 109.160 75.180 ;
    END
  END NN4BEG[15]
  PIN NN4BEG[1]
    DIRECTION OUTPUT ;
    USE SIGNAL ;
    ANTENNADIFFAREA 2.724000 ;
    PORT
      LAYER Metal2 ;
        RECT 81.880 74.780 82.280 75.180 ;
    END
  END NN4BEG[1]
  PIN NN4BEG[2]
    DIRECTION OUTPUT ;
    USE SIGNAL ;
    ANTENNADIFFAREA 2.724000 ;
    PORT
      LAYER Metal2 ;
        RECT 83.800 74.780 84.200 75.180 ;
    END
  END NN4BEG[2]
  PIN NN4BEG[3]
    DIRECTION OUTPUT ;
    USE SIGNAL ;
    ANTENNADIFFAREA 2.724000 ;
    PORT
      LAYER Metal2 ;
        RECT 85.720 74.780 86.120 75.180 ;
    END
  END NN4BEG[3]
  PIN NN4BEG[4]
    DIRECTION OUTPUT ;
    USE SIGNAL ;
    ANTENNADIFFAREA 2.724000 ;
    PORT
      LAYER Metal2 ;
        RECT 87.640 74.780 88.040 75.180 ;
    END
  END NN4BEG[4]
  PIN NN4BEG[5]
    DIRECTION OUTPUT ;
    USE SIGNAL ;
    ANTENNADIFFAREA 2.724000 ;
    PORT
      LAYER Metal2 ;
        RECT 89.560 74.780 89.960 75.180 ;
    END
  END NN4BEG[5]
  PIN NN4BEG[6]
    DIRECTION OUTPUT ;
    USE SIGNAL ;
    ANTENNADIFFAREA 2.724000 ;
    PORT
      LAYER Metal2 ;
        RECT 91.480 74.780 91.880 75.180 ;
    END
  END NN4BEG[6]
  PIN NN4BEG[7]
    DIRECTION OUTPUT ;
    USE SIGNAL ;
    ANTENNADIFFAREA 2.724000 ;
    PORT
      LAYER Metal2 ;
        RECT 93.400 74.780 93.800 75.180 ;
    END
  END NN4BEG[7]
  PIN NN4BEG[8]
    DIRECTION OUTPUT ;
    USE SIGNAL ;
    ANTENNADIFFAREA 2.724000 ;
    PORT
      LAYER Metal2 ;
        RECT 95.320 74.780 95.720 75.180 ;
    END
  END NN4BEG[8]
  PIN NN4BEG[9]
    DIRECTION OUTPUT ;
    USE SIGNAL ;
    ANTENNADIFFAREA 2.724000 ;
    PORT
      LAYER Metal2 ;
        RECT 97.240 74.780 97.640 75.180 ;
    END
  END NN4BEG[9]
  PIN S1END[0]
    DIRECTION INPUT ;
    USE SIGNAL ;
    ANTENNAGATEAREA 0.852800 ;
    ANTENNADIFFAREA 8.061600 ;
    PORT
      LAYER Metal2 ;
        RECT 113.560 74.780 113.960 75.180 ;
    END
  END S1END[0]
  PIN S1END[1]
    DIRECTION INPUT ;
    USE SIGNAL ;
    ANTENNAGATEAREA 0.852800 ;
    ANTENNADIFFAREA 8.061600 ;
    PORT
      LAYER Metal2 ;
        RECT 115.480 74.780 115.880 75.180 ;
    END
  END S1END[1]
  PIN S1END[2]
    DIRECTION INPUT ;
    USE SIGNAL ;
    ANTENNAGATEAREA 0.639600 ;
    ANTENNADIFFAREA 6.046200 ;
    PORT
      LAYER Metal2 ;
        RECT 117.400 74.780 117.800 75.180 ;
    END
  END S1END[2]
  PIN S1END[3]
    DIRECTION INPUT ;
    USE SIGNAL ;
    ANTENNAGATEAREA 0.639600 ;
    ANTENNADIFFAREA 6.046200 ;
    PORT
      LAYER Metal2 ;
        RECT 119.320 74.780 119.720 75.180 ;
    END
  END S1END[3]
  PIN S2END[0]
    DIRECTION INPUT ;
    USE SIGNAL ;
    ANTENNAGATEAREA 1.066000 ;
    ANTENNADIFFAREA 10.077000 ;
    PORT
      LAYER Metal2 ;
        RECT 139.480 74.780 139.880 75.180 ;
    END
  END S2END[0]
  PIN S2END[1]
    DIRECTION INPUT ;
    USE SIGNAL ;
    ANTENNAGATEAREA 0.852800 ;
    ANTENNADIFFAREA 8.061600 ;
    PORT
      LAYER Metal2 ;
        RECT 141.400 74.780 141.800 75.180 ;
    END
  END S2END[1]
  PIN S2END[2]
    DIRECTION INPUT ;
    USE SIGNAL ;
    ANTENNAGATEAREA 1.066000 ;
    ANTENNADIFFAREA 10.077000 ;
    PORT
      LAYER Metal2 ;
        RECT 143.320 74.780 143.720 75.180 ;
    END
  END S2END[2]
  PIN S2END[3]
    DIRECTION INPUT ;
    USE SIGNAL ;
    ANTENNAGATEAREA 0.852800 ;
    ANTENNADIFFAREA 8.061600 ;
    PORT
      LAYER Metal2 ;
        RECT 145.240 74.780 145.640 75.180 ;
    END
  END S2END[3]
  PIN S2END[4]
    DIRECTION INPUT ;
    USE SIGNAL ;
    ANTENNAGATEAREA 1.066000 ;
    ANTENNADIFFAREA 10.077000 ;
    PORT
      LAYER Metal2 ;
        RECT 147.160 74.780 147.560 75.180 ;
    END
  END S2END[4]
  PIN S2END[5]
    DIRECTION INPUT ;
    USE SIGNAL ;
    ANTENNAGATEAREA 0.852800 ;
    ANTENNADIFFAREA 8.061600 ;
    PORT
      LAYER Metal2 ;
        RECT 149.080 74.780 149.480 75.180 ;
    END
  END S2END[5]
  PIN S2END[6]
    DIRECTION INPUT ;
    USE SIGNAL ;
    ANTENNAGATEAREA 1.066000 ;
    ANTENNADIFFAREA 10.077000 ;
    PORT
      LAYER Metal2 ;
        RECT 151.000 74.780 151.400 75.180 ;
    END
  END S2END[6]
  PIN S2END[7]
    DIRECTION INPUT ;
    USE SIGNAL ;
    ANTENNAGATEAREA 0.852800 ;
    ANTENNADIFFAREA 8.061600 ;
    PORT
      LAYER Metal2 ;
        RECT 152.920 74.780 153.320 75.180 ;
    END
  END S2END[7]
  PIN S2MID[0]
    DIRECTION INPUT ;
    USE SIGNAL ;
    ANTENNAGATEAREA 1.246700 ;
    ANTENNADIFFAREA 12.092400 ;
    PORT
      LAYER Metal2 ;
        RECT 122.200 74.780 122.600 75.180 ;
    END
  END S2MID[0]
  PIN S2MID[1]
    DIRECTION INPUT ;
    USE SIGNAL ;
    ANTENNAGATEAREA 1.279200 ;
    ANTENNADIFFAREA 12.092400 ;
    PORT
      LAYER Metal2 ;
        RECT 124.120 74.780 124.520 75.180 ;
    END
  END S2MID[1]
  PIN S2MID[2]
    DIRECTION INPUT ;
    USE SIGNAL ;
    ANTENNAGATEAREA 1.246700 ;
    ANTENNADIFFAREA 12.092400 ;
    PORT
      LAYER Metal2 ;
        RECT 126.040 74.780 126.440 75.180 ;
    END
  END S2MID[2]
  PIN S2MID[3]
    DIRECTION INPUT ;
    USE SIGNAL ;
    ANTENNAGATEAREA 1.279200 ;
    ANTENNADIFFAREA 12.092400 ;
    PORT
      LAYER Metal2 ;
        RECT 127.960 74.780 128.360 75.180 ;
    END
  END S2MID[3]
  PIN S2MID[4]
    DIRECTION INPUT ;
    USE SIGNAL ;
    ANTENNAGATEAREA 1.033500 ;
    ANTENNADIFFAREA 10.077000 ;
    PORT
      LAYER Metal2 ;
        RECT 129.880 74.780 130.280 75.180 ;
    END
  END S2MID[4]
  PIN S2MID[5]
    DIRECTION INPUT ;
    USE SIGNAL ;
    ANTENNAGATEAREA 1.066000 ;
    ANTENNADIFFAREA 10.077000 ;
    PORT
      LAYER Metal2 ;
        RECT 131.800 74.780 132.200 75.180 ;
    END
  END S2MID[5]
  PIN S2MID[6]
    DIRECTION INPUT ;
    USE SIGNAL ;
    ANTENNAGATEAREA 1.033500 ;
    ANTENNADIFFAREA 10.077000 ;
    PORT
      LAYER Metal2 ;
        RECT 133.720 74.780 134.120 75.180 ;
    END
  END S2MID[6]
  PIN S2MID[7]
    DIRECTION INPUT ;
    USE SIGNAL ;
    ANTENNAGATEAREA 1.066000 ;
    ANTENNADIFFAREA 10.077000 ;
    PORT
      LAYER Metal2 ;
        RECT 135.640 74.780 136.040 75.180 ;
    END
  END S2MID[7]
  PIN S4END[0]
    DIRECTION INPUT ;
    USE SIGNAL ;
    ANTENNAGATEAREA 0.426400 ;
    ANTENNADIFFAREA 4.030800 ;
    PORT
      LAYER Metal2 ;
        RECT 157.720 74.780 158.120 75.180 ;
    END
  END S4END[0]
  PIN S4END[10]
    DIRECTION INPUT ;
    USE SIGNAL ;
    ANTENNAGATEAREA 0.639600 ;
    ANTENNADIFFAREA 6.046200 ;
    PORT
      LAYER Metal2 ;
        RECT 176.920 74.780 177.320 75.180 ;
    END
  END S4END[10]
  PIN S4END[11]
    DIRECTION INPUT ;
    USE SIGNAL ;
    ANTENNAGATEAREA 0.639600 ;
    ANTENNADIFFAREA 6.046200 ;
    PORT
      LAYER Metal2 ;
        RECT 178.840 74.780 179.240 75.180 ;
    END
  END S4END[11]
  PIN S4END[12]
    DIRECTION INPUT ;
    USE SIGNAL ;
    ANTENNAGATEAREA 0.852800 ;
    ANTENNADIFFAREA 8.061600 ;
    PORT
      LAYER Metal2 ;
        RECT 180.760 74.780 181.160 75.180 ;
    END
  END S4END[12]
  PIN S4END[13]
    DIRECTION INPUT ;
    USE SIGNAL ;
    ANTENNAGATEAREA 0.852800 ;
    ANTENNADIFFAREA 8.061600 ;
    PORT
      LAYER Metal2 ;
        RECT 182.680 74.780 183.080 75.180 ;
    END
  END S4END[13]
  PIN S4END[14]
    DIRECTION INPUT ;
    USE SIGNAL ;
    ANTENNAGATEAREA 0.852800 ;
    ANTENNADIFFAREA 8.061600 ;
    PORT
      LAYER Metal2 ;
        RECT 184.600 74.780 185.000 75.180 ;
    END
  END S4END[14]
  PIN S4END[15]
    DIRECTION INPUT ;
    USE SIGNAL ;
    ANTENNAGATEAREA 0.852800 ;
    ANTENNADIFFAREA 8.061600 ;
    PORT
      LAYER Metal2 ;
        RECT 186.520 74.780 186.920 75.180 ;
    END
  END S4END[15]
  PIN S4END[1]
    DIRECTION INPUT ;
    USE SIGNAL ;
    ANTENNAGATEAREA 0.426400 ;
    ANTENNADIFFAREA 4.030800 ;
    PORT
      LAYER Metal2 ;
        RECT 159.640 74.780 160.040 75.180 ;
    END
  END S4END[1]
  PIN S4END[2]
    DIRECTION INPUT ;
    USE SIGNAL ;
    ANTENNAGATEAREA 0.426400 ;
    ANTENNADIFFAREA 4.030800 ;
    PORT
      LAYER Metal2 ;
        RECT 161.560 74.780 161.960 75.180 ;
    END
  END S4END[2]
  PIN S4END[3]
    DIRECTION INPUT ;
    USE SIGNAL ;
    ANTENNAGATEAREA 0.426400 ;
    ANTENNADIFFAREA 4.030800 ;
    PORT
      LAYER Metal2 ;
        RECT 163.480 74.780 163.880 75.180 ;
    END
  END S4END[3]
  PIN S4END[4]
    DIRECTION INPUT ;
    USE SIGNAL ;
    ANTENNAGATEAREA 0.639600 ;
    ANTENNADIFFAREA 6.046200 ;
    PORT
      LAYER Metal2 ;
        RECT 165.400 74.780 165.800 75.180 ;
    END
  END S4END[4]
  PIN S4END[5]
    DIRECTION INPUT ;
    USE SIGNAL ;
    ANTENNAGATEAREA 0.426400 ;
    ANTENNADIFFAREA 4.030800 ;
    PORT
      LAYER Metal2 ;
        RECT 167.320 74.780 167.720 75.180 ;
    END
  END S4END[5]
  PIN S4END[6]
    DIRECTION INPUT ;
    USE SIGNAL ;
    ANTENNAGATEAREA 0.426400 ;
    ANTENNADIFFAREA 4.030800 ;
    PORT
      LAYER Metal2 ;
        RECT 169.240 74.780 169.640 75.180 ;
    END
  END S4END[6]
  PIN S4END[7]
    DIRECTION INPUT ;
    USE SIGNAL ;
    ANTENNAGATEAREA 0.426400 ;
    ANTENNADIFFAREA 4.030800 ;
    PORT
      LAYER Metal2 ;
        RECT 171.160 74.780 171.560 75.180 ;
    END
  END S4END[7]
  PIN S4END[8]
    DIRECTION INPUT ;
    USE SIGNAL ;
    ANTENNAGATEAREA 0.639600 ;
    ANTENNADIFFAREA 6.046200 ;
    PORT
      LAYER Metal2 ;
        RECT 173.080 74.780 173.480 75.180 ;
    END
  END S4END[8]
  PIN S4END[9]
    DIRECTION INPUT ;
    USE SIGNAL ;
    ANTENNAGATEAREA 0.639600 ;
    ANTENNADIFFAREA 6.046200 ;
    PORT
      LAYER Metal2 ;
        RECT 175.000 74.780 175.400 75.180 ;
    END
  END S4END[9]
  PIN SLOT_SOFT_RST_N
    DIRECTION INPUT ;
    USE SIGNAL ;
    ANTENNAGATEAREA 0.443300 ;
    ANTENNADIFFAREA 2.015400 ;
    PORT
      LAYER Metal2 ;
        RECT 202.840 0.000 203.240 0.400 ;
    END
  END SLOT_SOFT_RST_N
  PIN SS4END[0]
    DIRECTION INPUT ;
    USE SIGNAL ;
    ANTENNAGATEAREA 0.426400 ;
    ANTENNADIFFAREA 4.030800 ;
    PORT
      LAYER Metal2 ;
        RECT 192.280 74.780 192.680 75.180 ;
    END
  END SS4END[0]
  PIN SS4END[10]
    DIRECTION INPUT ;
    USE SIGNAL ;
    ANTENNAGATEAREA 0.639600 ;
    ANTENNADIFFAREA 6.046200 ;
    PORT
      LAYER Metal2 ;
        RECT 211.480 74.780 211.880 75.180 ;
    END
  END SS4END[10]
  PIN SS4END[11]
    DIRECTION INPUT ;
    USE SIGNAL ;
    ANTENNAGATEAREA 0.639600 ;
    ANTENNADIFFAREA 6.046200 ;
    PORT
      LAYER Metal2 ;
        RECT 213.400 74.780 213.800 75.180 ;
    END
  END SS4END[11]
  PIN SS4END[12]
    DIRECTION INPUT ;
    USE SIGNAL ;
    ANTENNAGATEAREA 0.852800 ;
    ANTENNADIFFAREA 8.061600 ;
    PORT
      LAYER Metal2 ;
        RECT 215.320 74.780 215.720 75.180 ;
    END
  END SS4END[12]
  PIN SS4END[13]
    DIRECTION INPUT ;
    USE SIGNAL ;
    ANTENNAGATEAREA 0.852800 ;
    ANTENNADIFFAREA 8.061600 ;
    PORT
      LAYER Metal2 ;
        RECT 217.240 74.780 217.640 75.180 ;
    END
  END SS4END[13]
  PIN SS4END[14]
    DIRECTION INPUT ;
    USE SIGNAL ;
    ANTENNAGATEAREA 0.852800 ;
    ANTENNADIFFAREA 8.061600 ;
    PORT
      LAYER Metal2 ;
        RECT 219.160 74.780 219.560 75.180 ;
    END
  END SS4END[14]
  PIN SS4END[15]
    DIRECTION INPUT ;
    USE SIGNAL ;
    ANTENNAGATEAREA 0.852800 ;
    ANTENNADIFFAREA 8.061600 ;
    PORT
      LAYER Metal2 ;
        RECT 221.080 74.780 221.480 75.180 ;
    END
  END SS4END[15]
  PIN SS4END[1]
    DIRECTION INPUT ;
    USE SIGNAL ;
    ANTENNAGATEAREA 0.426400 ;
    ANTENNADIFFAREA 4.030800 ;
    PORT
      LAYER Metal2 ;
        RECT 194.200 74.780 194.600 75.180 ;
    END
  END SS4END[1]
  PIN SS4END[2]
    DIRECTION INPUT ;
    USE SIGNAL ;
    ANTENNAGATEAREA 0.426400 ;
    ANTENNADIFFAREA 4.030800 ;
    PORT
      LAYER Metal2 ;
        RECT 196.120 74.780 196.520 75.180 ;
    END
  END SS4END[2]
  PIN SS4END[3]
    DIRECTION INPUT ;
    USE SIGNAL ;
    ANTENNAGATEAREA 0.426400 ;
    ANTENNADIFFAREA 4.030800 ;
    PORT
      LAYER Metal2 ;
        RECT 198.040 74.780 198.440 75.180 ;
    END
  END SS4END[3]
  PIN SS4END[4]
    DIRECTION INPUT ;
    USE SIGNAL ;
    ANTENNAGATEAREA 0.639600 ;
    ANTENNADIFFAREA 6.046200 ;
    PORT
      LAYER Metal2 ;
        RECT 199.960 74.780 200.360 75.180 ;
    END
  END SS4END[4]
  PIN SS4END[5]
    DIRECTION INPUT ;
    USE SIGNAL ;
    ANTENNAGATEAREA 0.426400 ;
    ANTENNADIFFAREA 4.030800 ;
    PORT
      LAYER Metal2 ;
        RECT 201.880 74.780 202.280 75.180 ;
    END
  END SS4END[5]
  PIN SS4END[6]
    DIRECTION INPUT ;
    USE SIGNAL ;
    ANTENNAGATEAREA 0.426400 ;
    ANTENNADIFFAREA 4.030800 ;
    PORT
      LAYER Metal2 ;
        RECT 203.800 74.780 204.200 75.180 ;
    END
  END SS4END[6]
  PIN SS4END[7]
    DIRECTION INPUT ;
    USE SIGNAL ;
    ANTENNAGATEAREA 0.426400 ;
    ANTENNADIFFAREA 4.030800 ;
    PORT
      LAYER Metal2 ;
        RECT 205.720 74.780 206.120 75.180 ;
    END
  END SS4END[7]
  PIN SS4END[8]
    DIRECTION INPUT ;
    USE SIGNAL ;
    ANTENNAGATEAREA 0.639600 ;
    ANTENNADIFFAREA 6.046200 ;
    PORT
      LAYER Metal2 ;
        RECT 207.640 74.780 208.040 75.180 ;
    END
  END SS4END[8]
  PIN SS4END[9]
    DIRECTION INPUT ;
    USE SIGNAL ;
    ANTENNAGATEAREA 0.639600 ;
    ANTENNADIFFAREA 6.046200 ;
    PORT
      LAYER Metal2 ;
        RECT 209.560 74.780 209.960 75.180 ;
    END
  END SS4END[9]
  PIN USR_IRQ
    DIRECTION OUTPUT ;
    USE SIGNAL ;
    ANTENNADIFFAREA 3.023500 ;
    PORT
      LAYER Metal2 ;
        RECT 263.320 0.000 263.720 0.400 ;
    END
  END USR_IRQ
  PIN UserCLK
    DIRECTION INPUT ;
    USE SIGNAL ;
    ANTENNAGATEAREA 2.901600 ;
    PORT
      LAYER Metal3 ;
        RECT 0.000 1.900 0.400 2.300 ;
    END
  END UserCLK
  PIN UserCLKo
    DIRECTION OUTPUT ;
    USE SIGNAL ;
    ANTENNADIFFAREA 2.724000 ;
    PORT
      LAYER Metal3 ;
        RECT 269.840 1.900 270.240 2.300 ;
    END
  END UserCLKo
  PIN VGND
    DIRECTION INOUT ;
    USE GROUND ;
    PORT
      LAYER Metal4 ;
        RECT 13.940 0.000 14.940 75.180 ;
    END
    PORT
      LAYER Metal4 ;
        RECT 63.940 0.000 64.940 75.180 ;
    END
    PORT
      LAYER Metal4 ;
        RECT 113.940 0.000 114.940 75.180 ;
    END
    PORT
      LAYER Metal4 ;
        RECT 163.940 0.000 164.940 75.180 ;
    END
    PORT
      LAYER Metal4 ;
        RECT 213.940 0.000 214.940 75.180 ;
    END
    PORT
      LAYER Metal4 ;
        RECT 263.940 0.000 264.940 75.180 ;
    END
  END VGND
  PIN VPWR
    DIRECTION INOUT ;
    USE POWER ;
    PORT
      LAYER Metal4 ;
        RECT 10.940 0.000 11.940 75.180 ;
    END
    PORT
      LAYER Metal4 ;
        RECT 60.940 0.000 61.940 75.180 ;
    END
    PORT
      LAYER Metal4 ;
        RECT 110.940 0.000 111.940 75.180 ;
    END
    PORT
      LAYER Metal4 ;
        RECT 160.940 0.000 161.940 75.180 ;
    END
    PORT
      LAYER Metal4 ;
        RECT 210.940 0.000 211.940 75.180 ;
    END
    PORT
      LAYER Metal4 ;
        RECT 260.940 0.000 261.940 75.180 ;
    END
  END VPWR
  OBS
      LAYER GatPoly ;
        RECT 1.440 3.630 268.800 68.190 ;
      LAYER Metal1 ;
        RECT 1.440 3.560 268.800 68.260 ;
      LAYER Metal2 ;
        RECT 0.375 74.570 1.990 74.860 ;
        RECT 2.810 74.570 3.910 74.860 ;
        RECT 4.730 74.570 5.830 74.860 ;
        RECT 6.650 74.570 7.750 74.860 ;
        RECT 8.570 74.570 10.630 74.860 ;
        RECT 11.450 74.570 12.550 74.860 ;
        RECT 13.370 74.570 14.470 74.860 ;
        RECT 15.290 74.570 16.390 74.860 ;
        RECT 17.210 74.570 18.310 74.860 ;
        RECT 19.130 74.570 20.230 74.860 ;
        RECT 21.050 74.570 22.150 74.860 ;
        RECT 22.970 74.570 24.070 74.860 ;
        RECT 24.890 74.570 26.950 74.860 ;
        RECT 27.770 74.570 28.870 74.860 ;
        RECT 29.690 74.570 30.790 74.860 ;
        RECT 31.610 74.570 32.710 74.860 ;
        RECT 33.530 74.570 34.630 74.860 ;
        RECT 35.450 74.570 36.550 74.860 ;
        RECT 37.370 74.570 38.470 74.860 ;
        RECT 39.290 74.570 40.390 74.860 ;
        RECT 41.210 74.570 45.190 74.860 ;
        RECT 46.010 74.570 47.110 74.860 ;
        RECT 47.930 74.570 49.030 74.860 ;
        RECT 49.850 74.570 50.950 74.860 ;
        RECT 51.770 74.570 52.870 74.860 ;
        RECT 53.690 74.570 54.790 74.860 ;
        RECT 55.610 74.570 56.710 74.860 ;
        RECT 57.530 74.570 58.630 74.860 ;
        RECT 59.450 74.570 60.550 74.860 ;
        RECT 61.370 74.570 62.470 74.860 ;
        RECT 63.290 74.570 64.390 74.860 ;
        RECT 65.210 74.570 66.310 74.860 ;
        RECT 67.130 74.570 68.230 74.860 ;
        RECT 69.050 74.570 70.150 74.860 ;
        RECT 70.970 74.570 72.070 74.860 ;
        RECT 72.890 74.570 73.990 74.860 ;
        RECT 74.810 74.570 79.750 74.860 ;
        RECT 80.570 74.570 81.670 74.860 ;
        RECT 82.490 74.570 83.590 74.860 ;
        RECT 84.410 74.570 85.510 74.860 ;
        RECT 86.330 74.570 87.430 74.860 ;
        RECT 88.250 74.570 89.350 74.860 ;
        RECT 90.170 74.570 91.270 74.860 ;
        RECT 92.090 74.570 93.190 74.860 ;
        RECT 94.010 74.570 95.110 74.860 ;
        RECT 95.930 74.570 97.030 74.860 ;
        RECT 97.850 74.570 98.950 74.860 ;
        RECT 99.770 74.570 100.870 74.860 ;
        RECT 101.690 74.570 102.790 74.860 ;
        RECT 103.610 74.570 104.710 74.860 ;
        RECT 105.530 74.570 106.630 74.860 ;
        RECT 107.450 74.570 108.550 74.860 ;
        RECT 109.370 74.570 113.350 74.860 ;
        RECT 114.170 74.570 115.270 74.860 ;
        RECT 116.090 74.570 117.190 74.860 ;
        RECT 118.010 74.570 119.110 74.860 ;
        RECT 119.930 74.570 121.990 74.860 ;
        RECT 122.810 74.570 123.910 74.860 ;
        RECT 124.730 74.570 125.830 74.860 ;
        RECT 126.650 74.570 127.750 74.860 ;
        RECT 128.570 74.570 129.670 74.860 ;
        RECT 130.490 74.570 131.590 74.860 ;
        RECT 132.410 74.570 133.510 74.860 ;
        RECT 134.330 74.570 135.430 74.860 ;
        RECT 136.250 74.570 139.270 74.860 ;
        RECT 140.090 74.570 141.190 74.860 ;
        RECT 142.010 74.570 143.110 74.860 ;
        RECT 143.930 74.570 145.030 74.860 ;
        RECT 145.850 74.570 146.950 74.860 ;
        RECT 147.770 74.570 148.870 74.860 ;
        RECT 149.690 74.570 150.790 74.860 ;
        RECT 151.610 74.570 152.710 74.860 ;
        RECT 153.530 74.570 157.510 74.860 ;
        RECT 158.330 74.570 159.430 74.860 ;
        RECT 160.250 74.570 161.350 74.860 ;
        RECT 162.170 74.570 163.270 74.860 ;
        RECT 164.090 74.570 165.190 74.860 ;
        RECT 166.010 74.570 167.110 74.860 ;
        RECT 167.930 74.570 169.030 74.860 ;
        RECT 169.850 74.570 170.950 74.860 ;
        RECT 171.770 74.570 172.870 74.860 ;
        RECT 173.690 74.570 174.790 74.860 ;
        RECT 175.610 74.570 176.710 74.860 ;
        RECT 177.530 74.570 178.630 74.860 ;
        RECT 179.450 74.570 180.550 74.860 ;
        RECT 181.370 74.570 182.470 74.860 ;
        RECT 183.290 74.570 184.390 74.860 ;
        RECT 185.210 74.570 186.310 74.860 ;
        RECT 187.130 74.570 192.070 74.860 ;
        RECT 192.890 74.570 193.990 74.860 ;
        RECT 194.810 74.570 195.910 74.860 ;
        RECT 196.730 74.570 197.830 74.860 ;
        RECT 198.650 74.570 199.750 74.860 ;
        RECT 200.570 74.570 201.670 74.860 ;
        RECT 202.490 74.570 203.590 74.860 ;
        RECT 204.410 74.570 205.510 74.860 ;
        RECT 206.330 74.570 207.430 74.860 ;
        RECT 208.250 74.570 209.350 74.860 ;
        RECT 210.170 74.570 211.270 74.860 ;
        RECT 212.090 74.570 213.190 74.860 ;
        RECT 214.010 74.570 215.110 74.860 ;
        RECT 215.930 74.570 217.030 74.860 ;
        RECT 217.850 74.570 218.950 74.860 ;
        RECT 219.770 74.570 220.870 74.860 ;
        RECT 221.690 74.570 225.670 74.860 ;
        RECT 226.490 74.570 230.470 74.860 ;
        RECT 231.290 74.570 232.390 74.860 ;
        RECT 233.210 74.570 234.310 74.860 ;
        RECT 235.130 74.570 236.230 74.860 ;
        RECT 237.050 74.570 238.150 74.860 ;
        RECT 238.970 74.570 240.070 74.860 ;
        RECT 240.890 74.570 241.990 74.860 ;
        RECT 242.810 74.570 243.910 74.860 ;
        RECT 244.730 74.570 245.830 74.860 ;
        RECT 246.650 74.570 247.750 74.860 ;
        RECT 248.570 74.570 249.670 74.860 ;
        RECT 250.490 74.570 251.590 74.860 ;
        RECT 252.410 74.570 253.510 74.860 ;
        RECT 254.330 74.570 255.430 74.860 ;
        RECT 256.250 74.570 257.350 74.860 ;
        RECT 258.170 74.570 259.270 74.860 ;
        RECT 260.090 74.570 261.190 74.860 ;
        RECT 262.010 74.570 263.110 74.860 ;
        RECT 263.930 74.570 265.030 74.860 ;
        RECT 265.850 74.570 266.950 74.860 ;
        RECT 0.375 0.610 267.465 74.570 ;
        RECT 0.375 0.275 7.750 0.610 ;
        RECT 8.570 0.275 14.470 0.610 ;
        RECT 15.290 0.275 21.190 0.610 ;
        RECT 22.010 0.275 27.910 0.610 ;
        RECT 28.730 0.275 34.630 0.610 ;
        RECT 35.450 0.275 41.350 0.610 ;
        RECT 42.170 0.275 48.070 0.610 ;
        RECT 48.890 0.275 54.790 0.610 ;
        RECT 55.610 0.275 61.510 0.610 ;
        RECT 62.330 0.275 68.230 0.610 ;
        RECT 69.050 0.275 74.950 0.610 ;
        RECT 75.770 0.275 81.670 0.610 ;
        RECT 82.490 0.275 88.390 0.610 ;
        RECT 89.210 0.275 95.110 0.610 ;
        RECT 95.930 0.275 101.830 0.610 ;
        RECT 102.650 0.275 108.550 0.610 ;
        RECT 109.370 0.275 115.270 0.610 ;
        RECT 116.090 0.275 121.990 0.610 ;
        RECT 122.810 0.275 128.710 0.610 ;
        RECT 129.530 0.275 135.430 0.610 ;
        RECT 136.250 0.275 148.870 0.610 ;
        RECT 149.690 0.275 155.590 0.610 ;
        RECT 156.410 0.275 162.310 0.610 ;
        RECT 163.130 0.275 169.030 0.610 ;
        RECT 169.850 0.275 175.750 0.610 ;
        RECT 176.570 0.275 182.470 0.610 ;
        RECT 183.290 0.275 189.190 0.610 ;
        RECT 190.010 0.275 195.910 0.610 ;
        RECT 196.730 0.275 202.630 0.610 ;
        RECT 203.450 0.275 209.350 0.610 ;
        RECT 210.170 0.275 216.070 0.610 ;
        RECT 216.890 0.275 222.790 0.610 ;
        RECT 223.610 0.275 229.510 0.610 ;
        RECT 230.330 0.275 236.230 0.610 ;
        RECT 237.050 0.275 242.950 0.610 ;
        RECT 243.770 0.275 249.670 0.610 ;
        RECT 250.490 0.275 256.390 0.610 ;
        RECT 257.210 0.275 263.110 0.610 ;
        RECT 263.930 0.275 267.465 0.610 ;
      LAYER Metal3 ;
        RECT 0.380 65.510 269.860 74.865 ;
        RECT 0.610 64.690 269.630 65.510 ;
        RECT 0.380 63.830 269.860 64.690 ;
        RECT 0.610 63.010 269.630 63.830 ;
        RECT 0.380 62.150 269.860 63.010 ;
        RECT 0.610 61.330 269.630 62.150 ;
        RECT 0.380 60.470 269.860 61.330 ;
        RECT 0.610 59.650 269.630 60.470 ;
        RECT 0.380 58.790 269.860 59.650 ;
        RECT 0.610 57.970 269.630 58.790 ;
        RECT 0.380 57.110 269.860 57.970 ;
        RECT 0.610 56.290 269.630 57.110 ;
        RECT 0.380 55.430 269.860 56.290 ;
        RECT 0.610 54.610 269.630 55.430 ;
        RECT 0.380 53.750 269.860 54.610 ;
        RECT 0.610 52.930 269.630 53.750 ;
        RECT 0.380 52.070 269.860 52.930 ;
        RECT 0.610 51.250 269.630 52.070 ;
        RECT 0.380 50.390 269.860 51.250 ;
        RECT 0.610 49.570 269.630 50.390 ;
        RECT 0.380 48.710 269.860 49.570 ;
        RECT 0.610 47.890 269.630 48.710 ;
        RECT 0.380 47.030 269.860 47.890 ;
        RECT 0.610 46.210 269.630 47.030 ;
        RECT 0.380 45.350 269.860 46.210 ;
        RECT 0.610 44.530 269.630 45.350 ;
        RECT 0.380 43.670 269.860 44.530 ;
        RECT 0.610 42.850 269.630 43.670 ;
        RECT 0.380 41.990 269.860 42.850 ;
        RECT 0.610 41.170 269.630 41.990 ;
        RECT 0.380 40.310 269.860 41.170 ;
        RECT 0.610 39.490 269.630 40.310 ;
        RECT 0.380 38.630 269.860 39.490 ;
        RECT 0.610 37.810 269.630 38.630 ;
        RECT 0.380 36.950 269.860 37.810 ;
        RECT 0.610 36.130 269.630 36.950 ;
        RECT 0.380 35.270 269.860 36.130 ;
        RECT 0.610 34.450 269.630 35.270 ;
        RECT 0.380 33.590 269.860 34.450 ;
        RECT 0.610 32.770 269.630 33.590 ;
        RECT 0.380 31.910 269.860 32.770 ;
        RECT 0.610 31.090 269.630 31.910 ;
        RECT 0.380 30.230 269.860 31.090 ;
        RECT 0.610 29.410 269.630 30.230 ;
        RECT 0.380 28.550 269.860 29.410 ;
        RECT 0.610 27.730 269.630 28.550 ;
        RECT 0.380 26.870 269.860 27.730 ;
        RECT 0.610 26.050 269.630 26.870 ;
        RECT 0.380 25.190 269.860 26.050 ;
        RECT 0.610 24.370 269.630 25.190 ;
        RECT 0.380 23.510 269.860 24.370 ;
        RECT 0.610 22.690 269.630 23.510 ;
        RECT 0.380 21.830 269.860 22.690 ;
        RECT 0.610 21.010 269.630 21.830 ;
        RECT 0.380 20.150 269.860 21.010 ;
        RECT 0.610 19.330 269.630 20.150 ;
        RECT 0.380 18.470 269.860 19.330 ;
        RECT 0.610 17.650 269.630 18.470 ;
        RECT 0.380 16.790 269.860 17.650 ;
        RECT 0.610 15.970 269.630 16.790 ;
        RECT 0.380 15.110 269.860 15.970 ;
        RECT 0.610 14.290 269.630 15.110 ;
        RECT 0.380 13.430 269.860 14.290 ;
        RECT 0.610 12.610 269.630 13.430 ;
        RECT 0.380 2.510 269.860 12.610 ;
        RECT 0.610 1.690 269.630 2.510 ;
        RECT 0.380 0.320 269.860 1.690 ;
      LAYER Metal4 ;
        RECT 49.820 5.735 60.730 74.905 ;
        RECT 62.150 5.735 63.730 74.905 ;
        RECT 65.150 5.735 110.730 74.905 ;
        RECT 112.150 5.735 113.730 74.905 ;
        RECT 115.150 5.735 160.730 74.905 ;
        RECT 162.150 5.735 163.730 74.905 ;
        RECT 165.150 5.735 210.730 74.905 ;
        RECT 212.150 5.735 213.730 74.905 ;
        RECT 215.150 5.735 252.580 74.905 ;
  END
END SOC_DEBUG_IO
END LIBRARY

